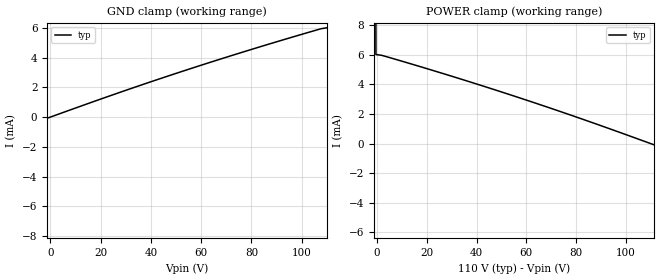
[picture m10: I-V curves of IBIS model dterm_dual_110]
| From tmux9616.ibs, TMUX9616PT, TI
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| dterm_dual_110
[Model]   dterm_dual_110
Model_type   Terminator
|   typ   min   max
C_comp   6.362683e-12   NA   NA
[Voltage Range]   110   NA   NA
[Temperature Range]   27   NA   NA
[Power Clamp Reference]   110   NA   NA
[GND Clamp Reference]   0   NA   NA
[GND Clamp]
|   Voltage   I(typ)   I(min)   I(max)
-115V     -1.54A     NA         NA
-112.7V   -587.9mA   NA         NA
-110.5V   -6.088mA   NA         NA
-78.64V   -4.488mA   NA         NA
-46.82V   -2.767mA   NA         NA
-21.82V   -1.321mA   NA         NA
28.18V    1.695mA    NA         NA
55.45V    3.245mA    NA         NA
89.55V    5.048mA    NA         NA
107.7V    5.953mA    NA         NA
110V      6.015mA    NA         NA
[POWER Clamp]
|   Voltage   I(typ)   I(min)   I(max)
-5V       1.104A     NA         NA
-2.727V   456mA      NA         NA
-455mV    6.026mA    NA         NA
1.818V    5.971mA    NA         NA
17.73V    5.186mA    NA         NA
54.09V    3.27mA     NA         NA
83.64V    1.589mA    NA         NA
156.4V    -2.741mA   NA         NA
188.2V    -4.464mA   NA         NA
220V      -6.066mA   NA         NA
